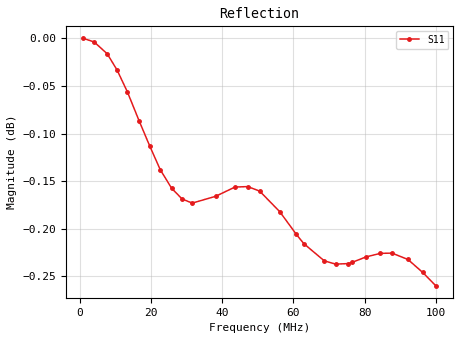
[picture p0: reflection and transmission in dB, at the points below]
# MHz S RI R 50.0
! SimSmith 18.4g
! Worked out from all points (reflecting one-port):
!   1000 points, 1 MHz to 100 MHz, reference 50 ohm
!   lowest |S11| = -0.3 dB at 100 MHz (marker M1), VSWR 66.90, Z = 0.748 + j0.746 ohm
!   phase of S11 starts at -9 deg and turns -893 deg over the sweep
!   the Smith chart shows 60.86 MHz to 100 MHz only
!   S11 on the Smith chart (normalised r, x): 60.86 MHz: 0.01, +0.08; 68.68 MHz: 0.02, +0.83; 76.51 MHz: 0.20, +3.75; 84.44 MHz: 0.10, -2.64; 92.17 MHz: 0.02, -0.69; 100 MHz: 0.01, +0.01
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1  0.9877 -0.1564
4.072072  0.8017 -0.597
7.738739  0.3453 -0.9365
10.51351  -0.0841 -0.9926
13.38739  -0.5096 -0.8529
16.65766  -0.8616 -0.4878
19.63063  -0.9861 -0.0444
22.6036  -0.8968 0.4056
25.77478  -0.5909 0.7844
28.74775  -0.1729 0.9654
31.62162  0.266 0.9435
38.16216  0.9457 0.2611
43.61261  0.8185 -0.5429
47.18018  0.4049 -0.8949
50.54955  -0.1028 -0.9763
56.1982  -0.8211 -0.5336
60.85586  -0.9644 0.1537
62.93694  -0.8625 0.4557
68.68469  -0.1739 0.9578
71.85586  0.3051 0.924
75.32432  0.7398 0.6322
76.51351  0.8444 0.484
80.47748  0.9689 -0.0988
84.44144  0.7301 -0.6452
87.71171  0.3189 -0.9207
92.17117  -0.3501 -0.9085
96.33333  -0.8299 -0.5062
100  -0.9701 0.029
